VERSION 5.7 ;
  NOWIREEXTENSIONATPIN ON ;
  DIVIDERCHAR "/" ;
  BUSBITCHARS "[]" ;
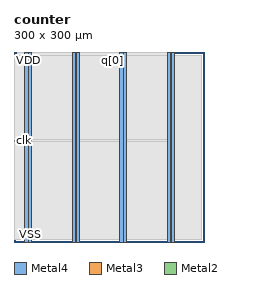
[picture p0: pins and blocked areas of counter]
MACRO counter
  CLASS BLOCK ;
  FOREIGN counter ;
  ORIGIN 0.000 0.000 ;
  SIZE 300.000 BY 300.000 ;
  PIN VDD
    DIRECTION INOUT ;
    USE POWER ;
    PORT
      LAYER Metal4 ;
        RECT 17.180 0.000 22.180 300.000 ;
    END
    PORT
      LAYER Metal4 ;
        RECT 92.180 0.000 97.180 300.000 ;
    END
    PORT
      LAYER Metal4 ;
        RECT 167.180 0.000 172.180 300.000 ;
    END
    PORT
      LAYER Metal4 ;
        RECT 242.180 0.000 247.180 300.000 ;
    END
  END VDD
  PIN VSS
    DIRECTION INOUT ;
    USE GROUND ;
    PORT
      LAYER Metal4 ;
        RECT 23.180 0.000 28.180 300.000 ;
    END
    PORT
      LAYER Metal4 ;
        RECT 98.180 0.000 103.180 300.000 ;
    END
    PORT
      LAYER Metal4 ;
        RECT 173.180 0.000 178.180 300.000 ;
    END
    PORT
      LAYER Metal4 ;
        RECT 248.180 0.000 253.180 300.000 ;
    END
  END VSS
  PIN clk
    DIRECTION INPUT ;
    USE SIGNAL ;
    ANTENNAGATEAREA 4.738000 ;
    ANTENNADIFFAREA 0.410400 ;
    PORT
      LAYER Metal3 ;
        RECT 0.000 160.160 0.560 160.720 ;
    END
  END clk
  PIN q[0]
    DIRECTION OUTPUT ;
    USE SIGNAL ;
    ANTENNADIFFAREA 0.897600 ;
    PORT
      LAYER Metal2 ;
        RECT 155.680 299.440 156.240 300.000 ;
    END
  END q[0]
  PIN q[1]
    DIRECTION OUTPUT ;
    USE SIGNAL ;
    ANTENNADIFFAREA 0.897600 ;
    PORT
      LAYER Metal2 ;
        RECT 156.800 299.440 157.360 300.000 ;
    END
  END q[1]
  PIN q[2]
    DIRECTION OUTPUT ;
    USE SIGNAL ;
    ANTENNADIFFAREA 0.897600 ;
    PORT
      LAYER Metal2 ;
        RECT 160.160 299.440 160.720 300.000 ;
    END
  END q[2]
  PIN q[3]
    DIRECTION OUTPUT ;
    USE SIGNAL ;
    ANTENNADIFFAREA 0.897600 ;
    PORT
      LAYER Metal3 ;
        RECT 0.000 161.280 0.560 161.840 ;
    END
  END q[3]
  PIN rst
    DIRECTION INPUT ;
    USE SIGNAL ;
    ANTENNAGATEAREA 0.396000 ;
    ANTENNADIFFAREA 0.410400 ;
    PORT
      LAYER Metal3 ;
        RECT 0.000 159.040 0.560 159.600 ;
    END
  END rst
  OBS
      LAYER Nwell ;
        RECT 2.930 3.490 296.670 294.430 ;
      LAYER Metal1 ;
        RECT 3.360 3.620 296.240 294.300 ;
      LAYER Metal2 ;
        RECT 5.180 299.140 155.380 299.440 ;
        RECT 157.660 299.140 159.860 299.440 ;
        RECT 161.020 299.140 252.900 299.440 ;
        RECT 5.180 3.730 252.900 299.140 ;
      LAYER Metal3 ;
        RECT 0.560 162.140 252.950 294.140 ;
        RECT 0.860 158.740 252.950 162.140 ;
        RECT 0.560 3.780 252.950 158.740 ;
  END
END counter
END LIBRARY

